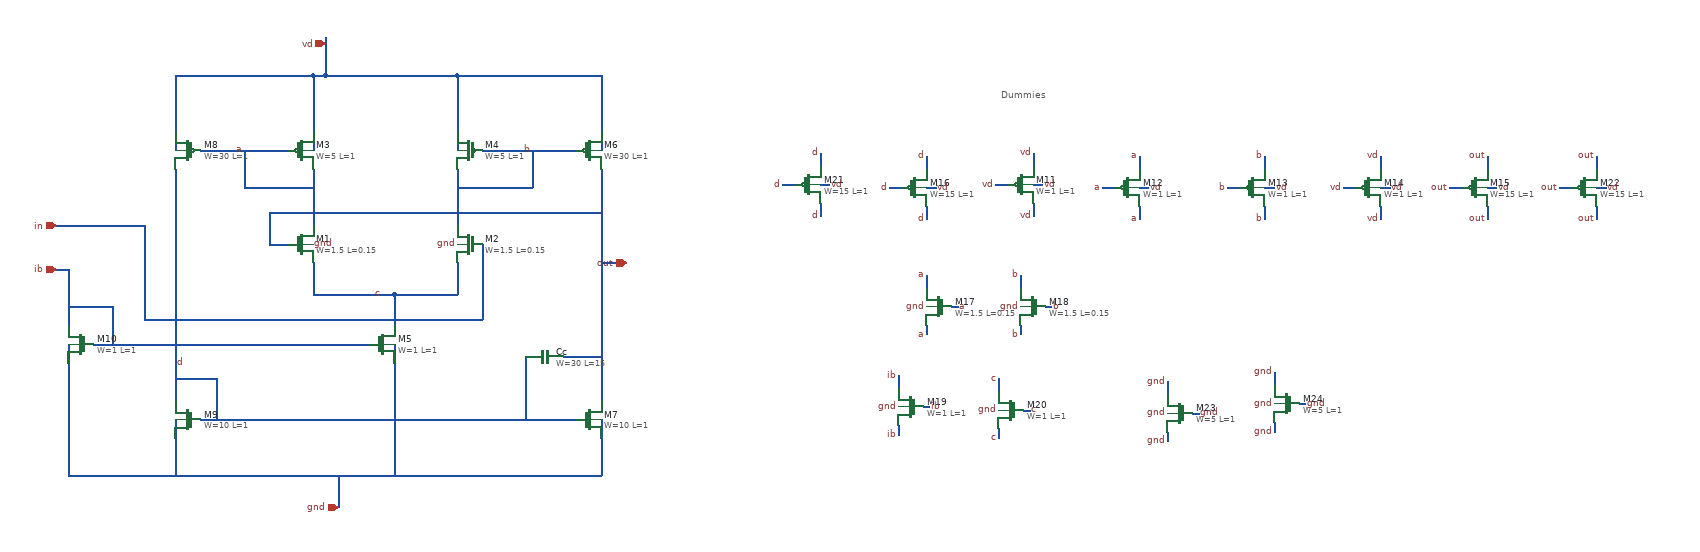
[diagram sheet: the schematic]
v {xschem version=3.4.5 file_version=1.2
* Copyright 2020 Stefan Frederik Schippers
* 
* Licensed under the Apache License, Version 2.0 (the "License");
* you may not use this file except in compliance with the License.
* You may obtain a copy of the License at
*
*     https://www.apache.org/licenses/LICENSE-2.0
*
* Unless required by applicable law or agreed to in writing, software
* distributed under the License is distributed on an "AS IS" BASIS,
* WITHOUT WARRANTIES OR CONDITIONS OF ANY KIND, either express or implied.
* See the License for the specific language governing permissions and
* limitations under the License.

}
G {}
K {}
V {}
S {}
E {}
T {Dummies} 1550 -1925 0 0 0.4 0.4 {}
N 30 -1635 60 -1635 { lab=ib}
N 470 -2005 470 -1945 { lab=vd}
N 450 -1945 470 -1945 {
lab=vd}
N 450 -1945 450 -1855 {
lab=vd}
N 450 -1855 450 -1825 {
lab=vd}
N 230 -1945 450 -1945 {
lab=vd}
N 230 -1945 230 -1855 {
lab=vd}
N 470 -1945 680 -1945 {
lab=vd}
N 680 -1945 680 -1855 {
lab=vd}
N 60 -1635 60 -1545 {
lab=ib}
N 60 -1515 60 -1485 {
lab=gnd}
N 230 -1855 230 -1825 {
lab=vd}
N 680 -1855 680 -1825 {
lab=vd}
N 230 -1795 230 -1425 {
lab=d}
N 230 -1395 230 -1365 {
lab=gnd}
N 270 -1395 870 -1395 {
lab=d}
N 450 -1795 450 -1705 {
lab=a}
N 680 -1795 680 -1705 {
lab=b}
N 270 -1825 410 -1825 {
lab=a}
N 340 -1765 450 -1765 {
lab=a}
N 340 -1825 340 -1765 {
lab=a}
N 720 -1825 870 -1825 {
lab=b}
N 680 -1765 800 -1765 {
lab=b}
N 800 -1825 800 -1765 {
lab=b}
N 680 -1945 910 -1945 {
lab=vd}
N 910 -1945 910 -1855 {
lab=vd}
N 910 -1855 910 -1825 {
lab=vd}
N 910 -1795 910 -1425 {
lab=out}
N 910 -1395 910 -1365 {
lab=gnd}
N 910 -1645 950 -1645 {
lab=out}
N 380 -1675 410 -1675 {
lab=out}
N 380 -1725 380 -1675 {
lab=out}
N 380 -1725 910 -1725 {
lab=out}
N 100 -1515 540 -1515 {
lab=ib}
N 450 -1645 450 -1595 {
lab=c}
N 450 -1595 580 -1595 {
lab=c}
N 580 -1595 580 -1545 {
lab=c}
N 580 -1515 580 -1485 {
lab=gnd}
N 580 -1595 680 -1595 {
lab=c}
N 680 -1645 680 -1595 {
lab=c}
N 720 -1675 720 -1555 {
lab=in}
N 180 -1555 720 -1555 {
lab=in}
N 180 -1705 180 -1555 {
lab=in}
N 30 -1705 180 -1705 {
lab=in}
N 60 -1485 60 -1305 {
lab=gnd}
N 60 -1305 910 -1305 {
lab=gnd}
N 910 -1365 910 -1305 {
lab=gnd}
N 230 -1365 230 -1305 {
lab=gnd}
N 580 -1485 580 -1305 {
lab=gnd}
N 490 -1305 490 -1255 {
lab=gnd}
N 60 -1575 130 -1575 {
lab=ib}
N 130 -1575 130 -1515 {
lab=ib}
N 230 -1460 295 -1460 {
lab=d}
N 295 -1460 295 -1395 {
lab=d}
N 790 -1495 790 -1395 {
lab=d}
N 850 -1495 910 -1495 {
lab=out}
N 1600 -1820 1600 -1800 {
lab=vd}
N 1600 -1770 1615 -1770 {
lab=vd}
N 1600 -1740 1600 -1720 {
lab=vd}
N 1540 -1770 1560 -1770 {
lab=vd}
N 1770 -1815 1770 -1795 {
lab=a}
N 1770 -1765 1785 -1765 {
lab=vd}
N 1770 -1735 1770 -1715 {
lab=a}
N 1710 -1765 1730 -1765 {
lab=a}
N 1970 -1815 1970 -1795 {
lab=b}
N 1970 -1765 1985 -1765 {
lab=vd}
N 1970 -1735 1970 -1715 {
lab=b}
N 1910 -1765 1930 -1765 {
lab=b}
N 2155 -1815 2155 -1795 {
lab=vd}
N 2155 -1765 2170 -1765 {
lab=vd}
N 2155 -1735 2155 -1715 {
lab=vd}
N 2095 -1765 2115 -1765 {
lab=vd}
N 2325 -1815 2325 -1795 {
lab=out}
N 2325 -1765 2340 -1765 {
lab=vd}
N 2325 -1735 2325 -1715 {
lab=out}
N 2265 -1765 2285 -1765 {
lab=out}
N 1430 -1815 1430 -1795 {
lab=d}
N 1430 -1765 1445 -1765 {
lab=vd}
N 1430 -1735 1430 -1715 {
lab=out}
N 1370 -1765 1390 -1765 {
lab=d}
N 1430 -1625 1430 -1605 {
lab=a}
N 1470 -1575 1480 -1575 {
lab=a}
N 1430 -1545 1430 -1530 {
lab=a}
N 1580 -1625 1580 -1605 {
lab=b}
N 1620 -1575 1630 -1575 {
lab=b}
N 1580 -1545 1580 -1530 {
lab=b}
N 1385 -1465 1385 -1445 {
lab=ib}
N 1425 -1415 1435 -1415 {
lab=ib}
N 1385 -1385 1385 -1370 {
lab=ib}
N 1545 -1460 1545 -1440 {
lab=c}
N 1585 -1410 1595 -1410 {
lab=c}
N 1545 -1380 1545 -1365 {
lab=c}
N 1260 -1820 1260 -1800 {
lab=d}
N 1260 -1770 1275 -1770 {
lab=vd}
N 1260 -1740 1260 -1720 {
lab=d}
N 1200 -1770 1220 -1770 {
lab=d}
N 2500 -1815 2500 -1795 {
lab=out}
N 2500 -1765 2515 -1765 {
lab=vd}
N 2500 -1735 2500 -1715 {
lab=out}
N 2440 -1765 2460 -1765 {
lab=out}
N 1815 -1455 1815 -1435 {
lab=gnd}
N 1855 -1405 1865 -1405 {
lab=gnd}
N 1815 -1375 1815 -1360 {
lab=gnd}
N 1985 -1470 1985 -1450 {
lab=gnd}
N 2025 -1420 2035 -1420 {
lab=gnd}
N 1985 -1390 1985 -1375 {
lab=gnd}
C {devices/iopin.sym} 470 -1995 3 0 {name=p2 lab=vd}
C {devices/iopin.sym} 40 -1635 2 0 {name=p1 lab=ib}
C {sky130_fd_pr/pfet_01v8.sym} 430 -1825 0 0 {name=M3
L=1
W=5
nf=5
mult=1
ad="'int((nf+1)/2) * W/nf * 0.29'" 
pd="'2*int((nf+1)/2) * (W/nf + 0.29)'"
as="'int((nf+2)/2) * W/nf * 0.29'" 
ps="'2*int((nf+2)/2) * (W/nf + 0.29)'"
nrd="'0.29 / W'" nrs="'0.29 / W'"
sa=0 sb=0 sd=0
model=pfet_01v8
spiceprefix=X
}
C {sky130_fd_pr/nfet_01v8.sym} 430 -1675 0 0 {name=M1
L=0.15
W=1.5
nf=1 
mult=1
ad="'int((nf+1)/2) * W/nf * 0.29'" 
pd="'2*int((nf+1)/2) * (W/nf + 0.29)'"
as="'int((nf+2)/2) * W/nf * 0.29'" 
ps="'2*int((nf+2)/2) * (W/nf + 0.29)'"
nrd="'0.29 / W'" nrs="'0.29 / W'"
sa=0 sb=0 sd=0
model=nfet_01v8
spiceprefix=X
}
C {sky130_fd_pr/nfet_01v8.sym} 700 -1675 0 1 {name=M2
L=0.15
W=1.5
nf=1 
mult=1
ad="'int((nf+1)/2) * W/nf * 0.29'" 
pd="'2*int((nf+1)/2) * (W/nf + 0.29)'"
as="'int((nf+2)/2) * W/nf * 0.29'" 
ps="'2*int((nf+2)/2) * (W/nf + 0.29)'"
nrd="'0.29 / W'" nrs="'0.29 / W'"
sa=0 sb=0 sd=0
model=nfet_01v8
spiceprefix=X
}
C {sky130_fd_pr/pfet_01v8.sym} 700 -1825 0 1 {name=M4
L=1
W=5
nf=5
mult=1
ad="'int((nf+1)/2) * W/nf * 0.29'" 
pd="'2*int((nf+1)/2) * (W/nf + 0.29)'"
as="'int((nf+2)/2) * W/nf * 0.29'" 
ps="'2*int((nf+2)/2) * (W/nf + 0.29)'"
nrd="'0.29 / W'" nrs="'0.29 / W'"
sa=0 sb=0 sd=0
model=pfet_01v8
spiceprefix=X
}
C {sky130_fd_pr/nfet_01v8.sym} 560 -1515 0 0 {name=M5
L=1
W=1
nf=1 
mult=1
ad="'int((nf+1)/2) * W/nf * 0.29'" 
pd="'2*int((nf+1)/2) * (W/nf + 0.29)'"
as="'int((nf+2)/2) * W/nf * 0.29'" 
ps="'2*int((nf+2)/2) * (W/nf + 0.29)'"
nrd="'0.29 / W'" nrs="'0.29 / W'"
sa=0 sb=0 sd=0
model=nfet_01v8
spiceprefix=X
}
C {sky130_fd_pr/pfet_01v8.sym} 890 -1825 0 0 {name=M6
L=1
W=30
nf=2
mult=1
ad="'int((nf+1)/2) * W/nf * 0.29'" 
pd="'2*int((nf+1)/2) * (W/nf + 0.29)'"
as="'int((nf+2)/2) * W/nf * 0.29'" 
ps="'2*int((nf+2)/2) * (W/nf + 0.29)'"
nrd="'0.29 / W'" nrs="'0.29 / W'"
sa=0 sb=0 sd=0
model=pfet_01v8
spiceprefix=X
}
C {sky130_fd_pr/nfet_01v8.sym} 890 -1395 0 0 {name=M7
L=1
W=10
nf=2
mult=1
ad="'int((nf+1)/2) * W/nf * 0.29'" 
pd="'2*int((nf+1)/2) * (W/nf + 0.29)'"
as="'int((nf+2)/2) * W/nf * 0.29'" 
ps="'2*int((nf+2)/2) * (W/nf + 0.29)'"
nrd="'0.29 / W'" nrs="'0.29 / W'"
sa=0 sb=0 sd=0
model=nfet_01v8
spiceprefix=X
}
C {sky130_fd_pr/pfet_01v8.sym} 250 -1825 0 1 {name=M8
L=1
W=30
nf=2
mult=1
ad="'int((nf+1)/2) * W/nf * 0.29'" 
pd="'2*int((nf+1)/2) * (W/nf + 0.29)'"
as="'int((nf+2)/2) * W/nf * 0.29'" 
ps="'2*int((nf+2)/2) * (W/nf + 0.29)'"
nrd="'0.29 / W'" nrs="'0.29 / W'"
sa=0 sb=0 sd=0
model=pfet_01v8
spiceprefix=X
}
C {sky130_fd_pr/nfet_01v8.sym} 250 -1395 0 1 {name=M9
L=1
W=10
nf=2
mult=1
ad="'int((nf+1)/2) * W/nf * 0.29'" 
pd="'2*int((nf+1)/2) * (W/nf + 0.29)'"
as="'int((nf+2)/2) * W/nf * 0.29'" 
ps="'2*int((nf+2)/2) * (W/nf + 0.29)'"
nrd="'0.29 / W'" nrs="'0.29 / W'"
sa=0 sb=0 sd=0
model=nfet_01v8
spiceprefix=X
}
C {sky130_fd_pr/nfet_01v8.sym} 80 -1515 0 1 {name=M10
L=1
W=1
nf=1 
mult=1
ad="'int((nf+1)/2) * W/nf * 0.29'" 
pd="'2*int((nf+1)/2) * (W/nf + 0.29)'"
as="'int((nf+2)/2) * W/nf * 0.29'" 
ps="'2*int((nf+2)/2) * (W/nf + 0.29)'"
nrd="'0.29 / W'" nrs="'0.29 / W'"
sa=0 sb=0 sd=0
model=nfet_01v8
spiceprefix=X
}
C {devices/iopin.sym} 950 -1645 0 0 {name=p3 lab=out}
C {devices/iopin.sym} 40 -1705 2 0 {name=p4 lab=in}
C {devices/iopin.sym} 490 -1255 1 0 {name=p5 lab=gnd}
C {devices/lab_pin.sym} 450 -1675 0 1 {name=l1 sig_type=std_logic lab=gnd}
C {devices/lab_pin.sym} 680 -1675 0 0 {name=l2 sig_type=std_logic lab=gnd}
C {sky130_fd_pr/cap_mim_m3_2.sym} 820 -1495 1 0 {name=Cc model=cap_mim_m3_2 W=30 L=15 MF=1 spiceprefix=X}
C {devices/lab_pin.sym} 340 -1825 3 1 {name=l3 sig_type=std_logic lab=a}
C {devices/lab_pin.sym} 800 -1825 3 1 {name=l4 sig_type=std_logic lab=b}
C {devices/lab_pin.sym} 560 -1595 3 1 {name=l5 sig_type=std_logic lab=c}
C {devices/lab_pin.sym} 230 -1485 0 1 {name=l6 sig_type=std_logic lab=d}
C {sky130_fd_pr/pfet_01v8.sym} 1580 -1770 0 0 {name=M11
L=1
W=1
nf=1
mult=1
ad="'int((nf+1)/2) * W/nf * 0.29'" 
pd="'2*int((nf+1)/2) * (W/nf + 0.29)'"
as="'int((nf+2)/2) * W/nf * 0.29'" 
ps="'2*int((nf+2)/2) * (W/nf + 0.29)'"
nrd="'0.29 / W'" nrs="'0.29 / W'"
sa=0 sb=0 sd=0
model=pfet_01v8
spiceprefix=X
}
C {devices/lab_pin.sym} 1615 -1770 0 1 {name=l7 sig_type=std_logic lab=vd}
C {devices/lab_pin.sym} 1600 -1820 3 1 {name=l8 sig_type=std_logic lab=vd}
C {devices/lab_pin.sym} 1540 -1770 2 1 {name=l9 sig_type=std_logic lab=vd}
C {devices/lab_pin.sym} 1600 -1720 1 1 {name=l10 sig_type=std_logic lab=vd}
C {sky130_fd_pr/pfet_01v8.sym} 1750 -1765 0 0 {name=M12
L=1
W=1
nf=1
mult=1
ad="'int((nf+1)/2) * W/nf * 0.29'" 
pd="'2*int((nf+1)/2) * (W/nf + 0.29)'"
as="'int((nf+2)/2) * W/nf * 0.29'" 
ps="'2*int((nf+2)/2) * (W/nf + 0.29)'"
nrd="'0.29 / W'" nrs="'0.29 / W'"
sa=0 sb=0 sd=0
model=pfet_01v8
spiceprefix=X
}
C {devices/lab_pin.sym} 1785 -1765 0 1 {name=l11 sig_type=std_logic lab=vd}
C {devices/lab_pin.sym} 1770 -1815 3 1 {name=l12 sig_type=std_logic lab=a}
C {devices/lab_pin.sym} 1710 -1765 2 1 {name=l13 sig_type=std_logic lab=a}
C {devices/lab_pin.sym} 1770 -1715 1 1 {name=l14 sig_type=std_logic lab=a}
C {sky130_fd_pr/pfet_01v8.sym} 1950 -1765 0 0 {name=M13
L=1
W=1
nf=1
mult=1
ad="'int((nf+1)/2) * W/nf * 0.29'" 
pd="'2*int((nf+1)/2) * (W/nf + 0.29)'"
as="'int((nf+2)/2) * W/nf * 0.29'" 
ps="'2*int((nf+2)/2) * (W/nf + 0.29)'"
nrd="'0.29 / W'" nrs="'0.29 / W'"
sa=0 sb=0 sd=0
model=pfet_01v8
spiceprefix=X
}
C {devices/lab_pin.sym} 1985 -1765 0 1 {name=l15 sig_type=std_logic lab=vd}
C {devices/lab_pin.sym} 1970 -1815 3 1 {name=l16 sig_type=std_logic lab=b}
C {devices/lab_pin.sym} 1910 -1765 2 1 {name=l17 sig_type=std_logic lab=b}
C {devices/lab_pin.sym} 1970 -1715 1 1 {name=l18 sig_type=std_logic lab=b}
C {sky130_fd_pr/pfet_01v8.sym} 2135 -1765 0 0 {name=M14
L=1
W=1
nf=1
mult=1
ad="'int((nf+1)/2) * W/nf * 0.29'" 
pd="'2*int((nf+1)/2) * (W/nf + 0.29)'"
as="'int((nf+2)/2) * W/nf * 0.29'" 
ps="'2*int((nf+2)/2) * (W/nf + 0.29)'"
nrd="'0.29 / W'" nrs="'0.29 / W'"
sa=0 sb=0 sd=0
model=pfet_01v8
spiceprefix=X
}
C {devices/lab_pin.sym} 2170 -1765 0 1 {name=l19 sig_type=std_logic lab=vd}
C {devices/lab_pin.sym} 2155 -1815 3 1 {name=l20 sig_type=std_logic lab=vd}
C {devices/lab_pin.sym} 2095 -1765 2 1 {name=l21 sig_type=std_logic lab=vd}
C {devices/lab_pin.sym} 2155 -1715 1 1 {name=l22 sig_type=std_logic lab=vd}
C {sky130_fd_pr/pfet_01v8.sym} 2305 -1765 0 0 {name=M15
L=1
W=15
nf=1
mult=1
ad="'int((nf+1)/2) * W/nf * 0.29'" 
pd="'2*int((nf+1)/2) * (W/nf + 0.29)'"
as="'int((nf+2)/2) * W/nf * 0.29'" 
ps="'2*int((nf+2)/2) * (W/nf + 0.29)'"
nrd="'0.29 / W'" nrs="'0.29 / W'"
sa=0 sb=0 sd=0
model=pfet_01v8
spiceprefix=X
}
C {devices/lab_pin.sym} 2340 -1765 0 1 {name=l23 sig_type=std_logic lab=vd}
C {devices/lab_pin.sym} 2325 -1815 3 1 {name=l24 sig_type=std_logic lab=out}
C {devices/lab_pin.sym} 2265 -1765 2 1 {name=l25 sig_type=std_logic lab=out}
C {devices/lab_pin.sym} 2325 -1715 1 1 {name=l26 sig_type=std_logic lab=out}
C {sky130_fd_pr/pfet_01v8.sym} 1410 -1765 0 0 {name=M16
L=1
W=15
nf=1
mult=1
ad="'int((nf+1)/2) * W/nf * 0.29'" 
pd="'2*int((nf+1)/2) * (W/nf + 0.29)'"
as="'int((nf+2)/2) * W/nf * 0.29'" 
ps="'2*int((nf+2)/2) * (W/nf + 0.29)'"
nrd="'0.29 / W'" nrs="'0.29 / W'"
sa=0 sb=0 sd=0
model=pfet_01v8
spiceprefix=X
}
C {devices/lab_pin.sym} 1445 -1765 0 1 {name=l27 sig_type=std_logic lab=vd}
C {devices/lab_pin.sym} 1430 -1815 3 1 {name=l28 sig_type=std_logic lab=d}
C {devices/lab_pin.sym} 1370 -1765 2 1 {name=l29 sig_type=std_logic lab=d}
C {devices/lab_pin.sym} 1430 -1715 1 1 {name=l30 sig_type=std_logic lab=d}
C {sky130_fd_pr/nfet_01v8.sym} 1450 -1575 0 1 {name=M17
L=0.15
W=1.5
nf=1 
mult=1
ad="'int((nf+1)/2) * W/nf * 0.29'" 
pd="'2*int((nf+1)/2) * (W/nf + 0.29)'"
as="'int((nf+2)/2) * W/nf * 0.29'" 
ps="'2*int((nf+2)/2) * (W/nf + 0.29)'"
nrd="'0.29 / W'" nrs="'0.29 / W'"
sa=0 sb=0 sd=0
model=nfet_01v8
spiceprefix=X
}
C {devices/lab_pin.sym} 1430 -1575 0 0 {name=l31 sig_type=std_logic lab=gnd}
C {devices/lab_pin.sym} 1430 -1625 1 0 {name=l32 sig_type=std_logic lab=a}
C {devices/lab_pin.sym} 1480 -1575 2 0 {name=l33 sig_type=std_logic lab=a}
C {devices/lab_pin.sym} 1430 -1530 3 0 {name=l34 sig_type=std_logic lab=a}
C {sky130_fd_pr/nfet_01v8.sym} 1600 -1575 0 1 {name=M18
L=0.15
W=1.5
nf=1 
mult=1
ad="'int((nf+1)/2) * W/nf * 0.29'" 
pd="'2*int((nf+1)/2) * (W/nf + 0.29)'"
as="'int((nf+2)/2) * W/nf * 0.29'" 
ps="'2*int((nf+2)/2) * (W/nf + 0.29)'"
nrd="'0.29 / W'" nrs="'0.29 / W'"
sa=0 sb=0 sd=0
model=nfet_01v8
spiceprefix=X
}
C {devices/lab_pin.sym} 1580 -1575 0 0 {name=l35 sig_type=std_logic lab=gnd}
C {devices/lab_pin.sym} 1580 -1625 1 0 {name=l36 sig_type=std_logic lab=b}
C {devices/lab_pin.sym} 1630 -1575 2 0 {name=l37 sig_type=std_logic lab=b}
C {devices/lab_pin.sym} 1580 -1530 3 0 {name=l38 sig_type=std_logic lab=b}
C {sky130_fd_pr/nfet_01v8.sym} 1405 -1415 0 1 {name=M19
L=1
W=1
nf=1 
mult=1
ad="'int((nf+1)/2) * W/nf * 0.29'" 
pd="'2*int((nf+1)/2) * (W/nf + 0.29)'"
as="'int((nf+2)/2) * W/nf * 0.29'" 
ps="'2*int((nf+2)/2) * (W/nf + 0.29)'"
nrd="'0.29 / W'" nrs="'0.29 / W'"
sa=0 sb=0 sd=0
model=nfet_01v8
spiceprefix=X
}
C {devices/lab_pin.sym} 1385 -1415 0 0 {name=l39 sig_type=std_logic lab=gnd}
C {devices/lab_pin.sym} 1385 -1465 1 0 {name=l40 sig_type=std_logic lab=ib}
C {devices/lab_pin.sym} 1435 -1415 2 0 {name=l41 sig_type=std_logic lab=ib}
C {devices/lab_pin.sym} 1385 -1370 3 0 {name=l42 sig_type=std_logic lab=ib}
C {sky130_fd_pr/nfet_01v8.sym} 1565 -1410 0 1 {name=M20
L=1
W=1
nf=1 
mult=1
ad="'int((nf+1)/2) * W/nf * 0.29'" 
pd="'2*int((nf+1)/2) * (W/nf + 0.29)'"
as="'int((nf+2)/2) * W/nf * 0.29'" 
ps="'2*int((nf+2)/2) * (W/nf + 0.29)'"
nrd="'0.29 / W'" nrs="'0.29 / W'"
sa=0 sb=0 sd=0
model=nfet_01v8
spiceprefix=X
}
C {devices/lab_pin.sym} 1545 -1410 0 0 {name=l43 sig_type=std_logic lab=gnd}
C {devices/lab_pin.sym} 1545 -1460 1 0 {name=l44 sig_type=std_logic lab=c}
C {devices/lab_pin.sym} 1595 -1410 2 0 {name=l45 sig_type=std_logic lab=c}
C {devices/lab_pin.sym} 1545 -1365 3 0 {name=l46 sig_type=std_logic lab=c}
C {sky130_fd_pr/pfet_01v8.sym} 1240 -1770 0 0 {name=M21
L=1
W=15
nf=1
mult=1
ad="'int((nf+1)/2) * W/nf * 0.29'" 
pd="'2*int((nf+1)/2) * (W/nf + 0.29)'"
as="'int((nf+2)/2) * W/nf * 0.29'" 
ps="'2*int((nf+2)/2) * (W/nf + 0.29)'"
nrd="'0.29 / W'" nrs="'0.29 / W'"
sa=0 sb=0 sd=0
model=pfet_01v8
spiceprefix=X
}
C {devices/lab_pin.sym} 1275 -1770 0 1 {name=l47 sig_type=std_logic lab=vd}
C {devices/lab_pin.sym} 1260 -1820 3 1 {name=l48 sig_type=std_logic lab=d}
C {devices/lab_pin.sym} 1200 -1770 2 1 {name=l49 sig_type=std_logic lab=d}
C {devices/lab_pin.sym} 1260 -1720 1 1 {name=l50 sig_type=std_logic lab=d}
C {sky130_fd_pr/pfet_01v8.sym} 2480 -1765 0 0 {name=M22
L=1
W=15
nf=1
mult=1
ad="'int((nf+1)/2) * W/nf * 0.29'" 
pd="'2*int((nf+1)/2) * (W/nf + 0.29)'"
as="'int((nf+2)/2) * W/nf * 0.29'" 
ps="'2*int((nf+2)/2) * (W/nf + 0.29)'"
nrd="'0.29 / W'" nrs="'0.29 / W'"
sa=0 sb=0 sd=0
model=pfet_01v8
spiceprefix=X
}
C {devices/lab_pin.sym} 2515 -1765 0 1 {name=l51 sig_type=std_logic lab=vd}
C {devices/lab_pin.sym} 2500 -1815 3 1 {name=l52 sig_type=std_logic lab=out}
C {devices/lab_pin.sym} 2440 -1765 2 1 {name=l53 sig_type=std_logic lab=out}
C {devices/lab_pin.sym} 2500 -1715 1 1 {name=l54 sig_type=std_logic lab=out}
C {sky130_fd_pr/nfet_01v8.sym} 1835 -1405 0 1 {name=M23
L=1
W=5
nf=1 
mult=1
ad="'int((nf+1)/2) * W/nf * 0.29'" 
pd="'2*int((nf+1)/2) * (W/nf + 0.29)'"
as="'int((nf+2)/2) * W/nf * 0.29'" 
ps="'2*int((nf+2)/2) * (W/nf + 0.29)'"
nrd="'0.29 / W'" nrs="'0.29 / W'"
sa=0 sb=0 sd=0
model=nfet_01v8
spiceprefix=X
}
C {devices/lab_pin.sym} 1815 -1405 0 0 {name=l55 sig_type=std_logic lab=gnd}
C {devices/lab_pin.sym} 1815 -1455 1 0 {name=l56 sig_type=std_logic lab=gnd}
C {devices/lab_pin.sym} 1865 -1405 2 0 {name=l57 sig_type=std_logic lab=gnd}
C {devices/lab_pin.sym} 1815 -1360 3 0 {name=l58 sig_type=std_logic lab=gnd}
C {sky130_fd_pr/nfet_01v8.sym} 2005 -1420 0 1 {name=M24
L=1
W=5
nf=1 
mult=1
ad="'int((nf+1)/2) * W/nf * 0.29'" 
pd="'2*int((nf+1)/2) * (W/nf + 0.29)'"
as="'int((nf+2)/2) * W/nf * 0.29'" 
ps="'2*int((nf+2)/2) * (W/nf + 0.29)'"
nrd="'0.29 / W'" nrs="'0.29 / W'"
sa=0 sb=0 sd=0
model=nfet_01v8
spiceprefix=X
}
C {devices/lab_pin.sym} 1985 -1420 0 0 {name=l59 sig_type=std_logic lab=gnd}
C {devices/lab_pin.sym} 1985 -1470 1 0 {name=l60 sig_type=std_logic lab=gnd}
C {devices/lab_pin.sym} 2035 -1420 2 0 {name=l61 sig_type=std_logic lab=gnd}
C {devices/lab_pin.sym} 1985 -1375 3 0 {name=l62 sig_type=std_logic lab=gnd}
